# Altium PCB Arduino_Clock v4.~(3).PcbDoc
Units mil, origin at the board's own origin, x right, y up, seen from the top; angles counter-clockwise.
Board outline 6000 x 4000 mil, 2 copper layers (Top Layer, Bottom Layer); 29 components, 36 nets, 120 pads, 14 vias.
Unrouted connection lines stored in the file: 76.

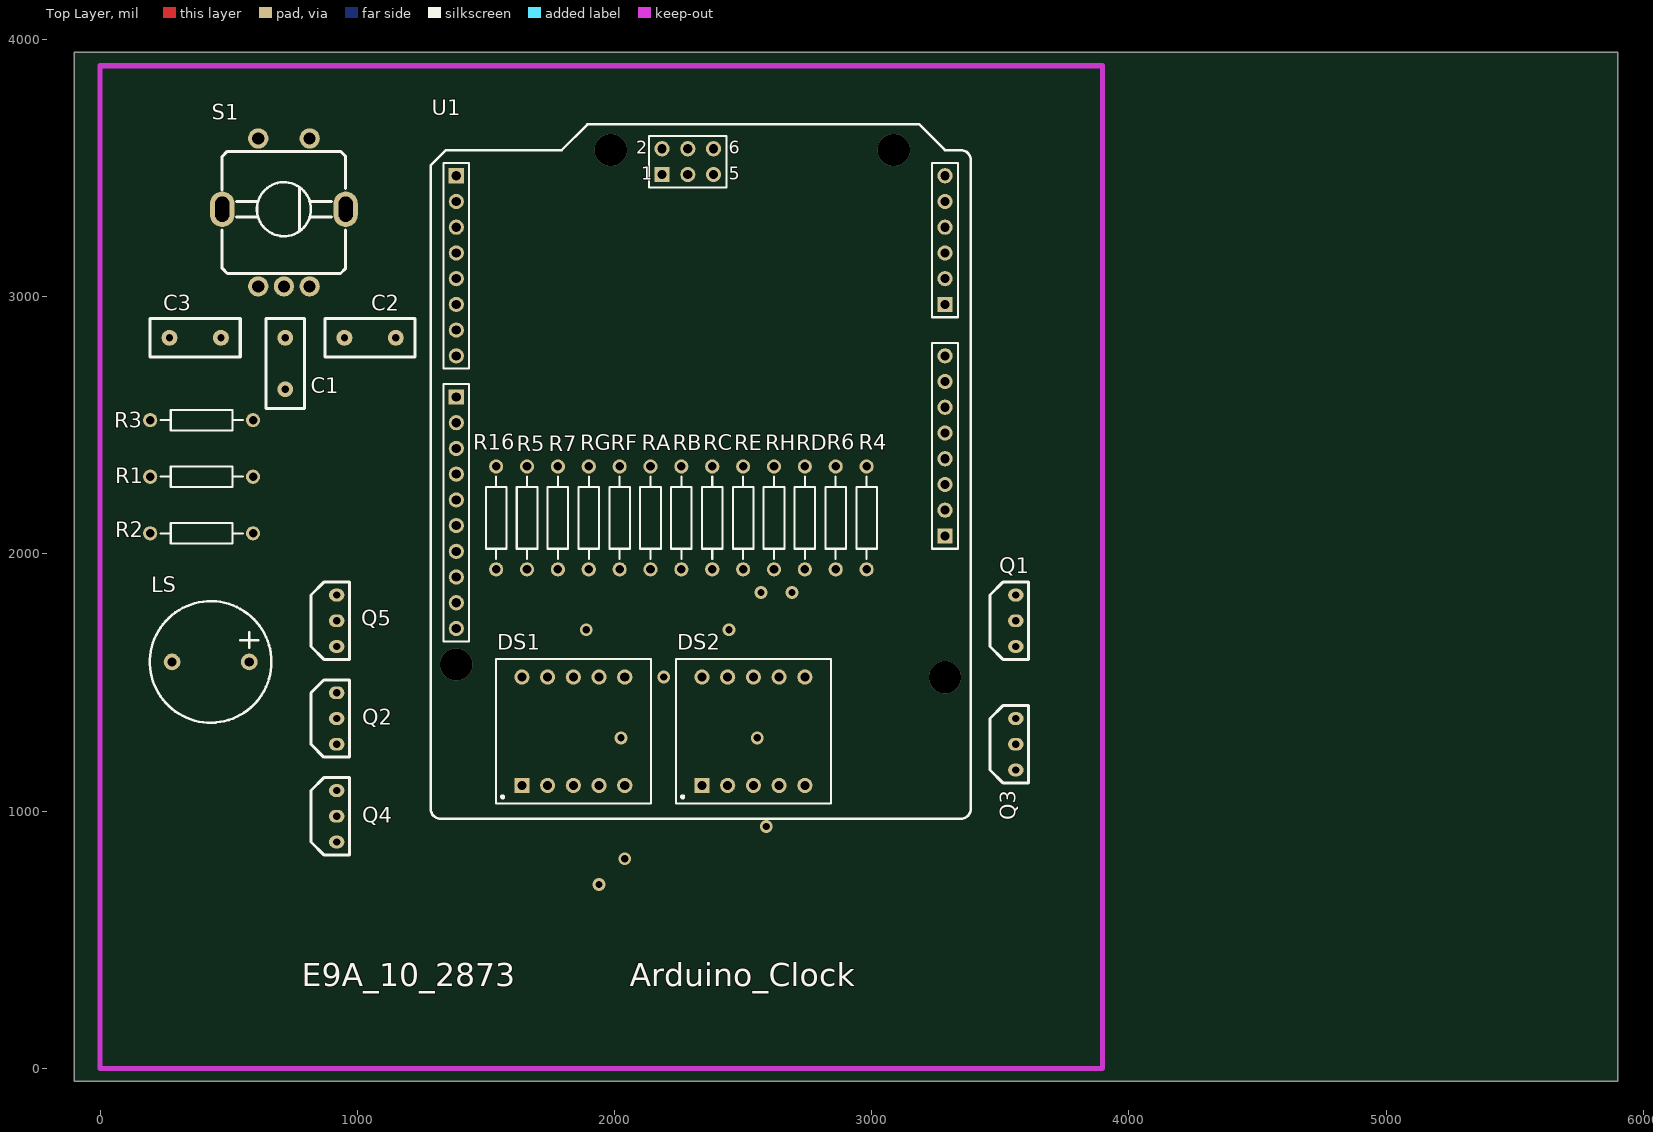
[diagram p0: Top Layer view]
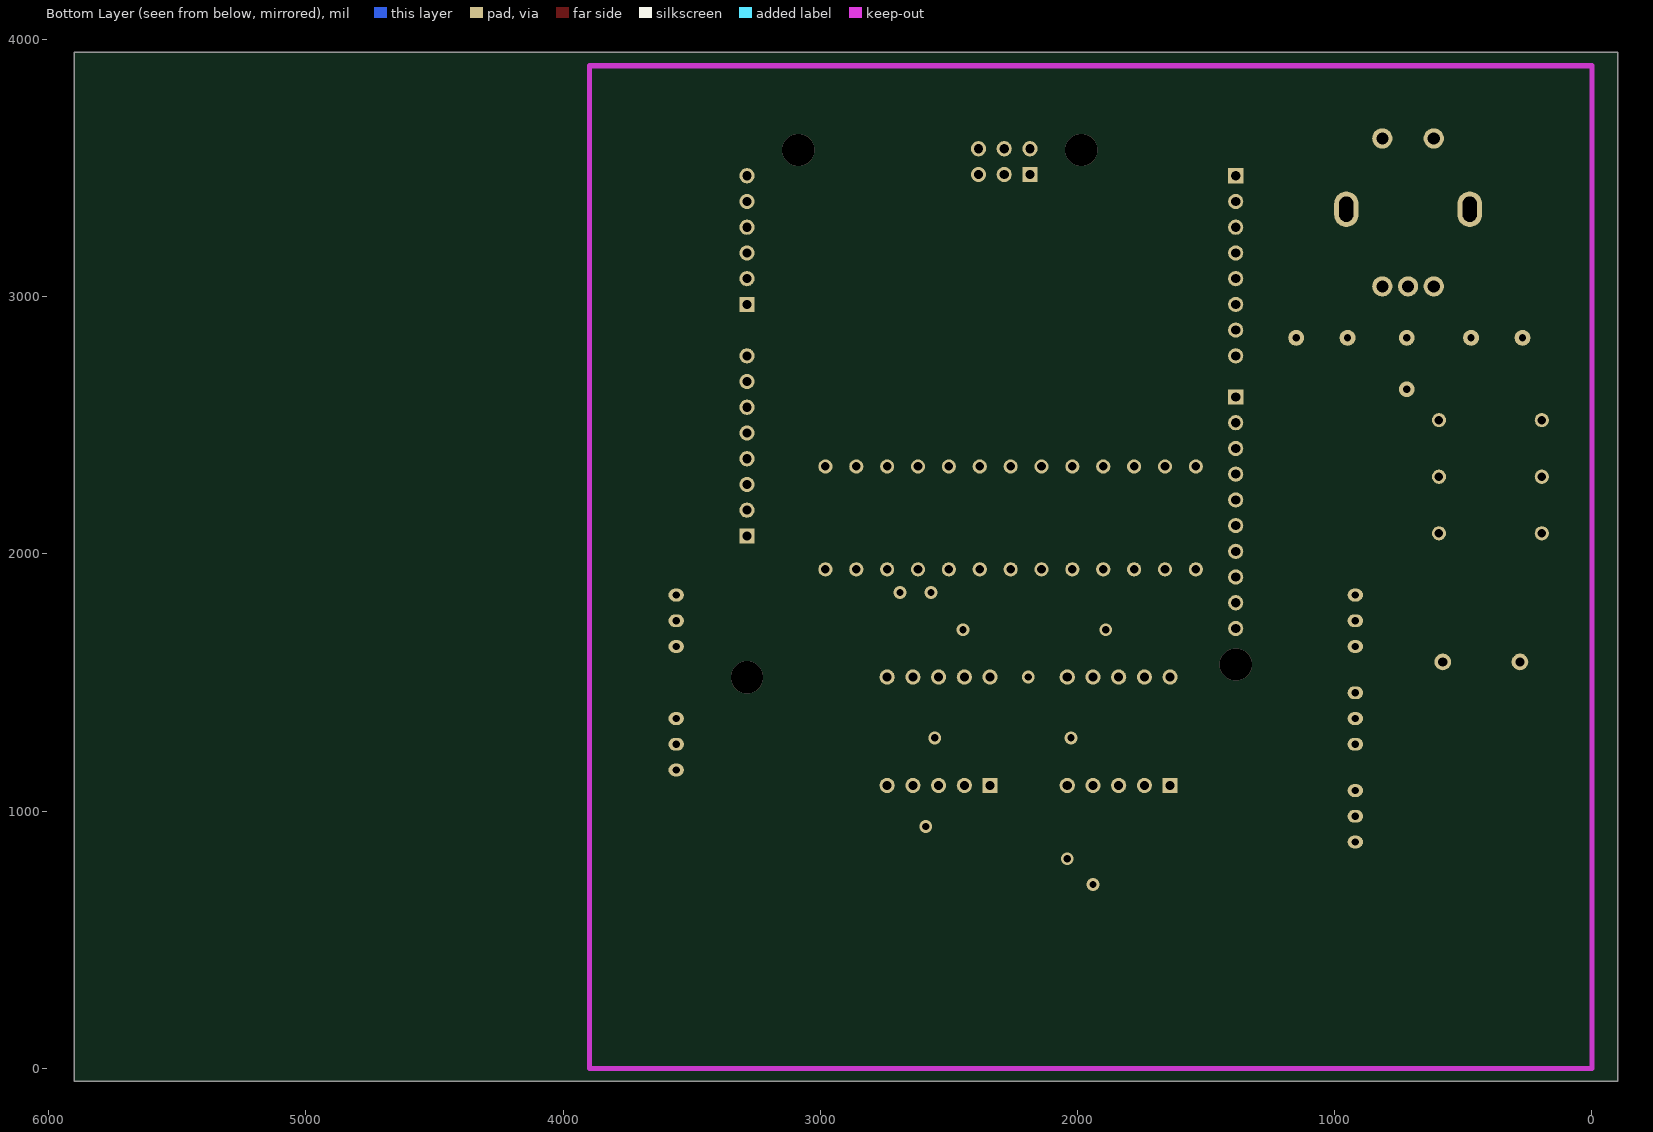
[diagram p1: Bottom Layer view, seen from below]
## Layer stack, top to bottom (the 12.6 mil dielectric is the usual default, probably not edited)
Top Layer: signal copper 1.4
Dielectric: dielectric 12.6, FR-4, Dk 4.8
Bottom Layer: signal copper 1.4

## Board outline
-100,-50 5900,-50 5900,3950 -100,3950

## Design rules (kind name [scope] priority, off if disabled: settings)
Clearance [All] p1 off: gap=10
DiffPairsRouting [All] p1 off: maxlimit=10 minlimit=10 mostfreqgap=10 maxuncoupledlength=500
FanoutControl Fanout_BGA [IsBGA] p1 off: bgadir=Out bgaviamode=Centered fanoutstyle=Auto fanoutdirection=Alternating viagrid=1 // Fanout_BGA (Default Rule)
FanoutControl Fanout_LCC [IsLCC] p2 off: bgadir=Out bgaviamode=Centered fanoutstyle=Auto fanoutdirection=Alternating viagrid=1 // Fanout_LCC (Default Rule)
FanoutControl Fanout_SOIC [IsSOIC] p3 off: bgadir=Out bgaviamode=Centered fanoutstyle=Auto fanoutdirection=Alternating viagrid=1 // Fanout_SOIC (Default Rule)
FanoutControl Fanout_Small [(CompPinCount < 5)] p4 off: bgadir=Out bgaviamode=Centered fanoutstyle=Auto fanoutdirection=OutThenIn viagrid=1 // Fanout_Small (Default Rule)
FanoutControl Fanout_Default [All] p5 off: bgadir=Out bgaviamode=Centered fanoutstyle=Auto fanoutdirection=Alternating viagrid=1 // Fanout_Default (Default Rule)
HoleSize [All] p1 off: absolutevalues=TRUE maxlimit=100 minlimit=1 maxpercent=80.000 minpercent=20.000
HoleToHoleClearance [All] p1 off: gap=10 allowstackedmicrovias=TRUE
LayerPairs [All] p1 off: enforce=TRUE
MinimumSolderMaskSliver [All] p1 off: minsoldermaskwidth=10
NetAntennae [All] p1 off: netantennaetolerance=0
PolygonConnect [All] p1: connectstyle=Relief reliefconductorwidth=10 reliefentries=4 polygonreliefangle="90 Angle"
RoomDefinition "Arduino_Clock v2" [InComponentClass('Arduino_Clock v2')] p1: confinementstyle=ConfineIn formatcopy=TRUE lockcomponents=FALSE outline 5825,-125 14900,-125 14900,2725 5825,2725
RoutingCorners [All] p1 off: cornerstyle=45-Degree minsetback=100 maxsetback=100
RoutingLayers [All] p1 off: top layer_v5=TRUE bottom layer_v5=TRUE
RoutingPriority [All] p1 off: routingpriority=0
RoutingTopology [All] p1 off: topology=Shortest
RoutingVias [All] p1 off: holewidth=28 width=50 viastyle="Through Hole" minholewidth=28 minwidth=50 maxholewidth=28 maxwidth=50
ShortCircuit [All] p1 off: allowed=FALSE
SilkToSilkClearance [All] p1 off: silktosilkclearance=10
SilkscreenOverComponentPads [All] p1 off: minsilkscreentomaskgap=10
SolderMaskExpansion [All] p1: expansion=4
TestPointUsage [All] p1 off: valid=0 allowmultiple=FALSE
Testpoint [All] p1 off: side=15 testpointundercomponent=TRUE minsize=40 maxsize=100 preferedsize=60 minholesize=0 maxholesize=40 preferedholesize=32 testpointgrid=1 style=1023 order=0123456789
UnRoutedNet [All] p1 off:
Width [All] p1 off: maxlimit=50 minlimit=10 preferedwidth=10
5 further rules are at their usual default settings.

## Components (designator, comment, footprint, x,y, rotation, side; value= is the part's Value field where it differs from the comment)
C1 "Cap" RAD0.2 720,2840 r270 top
C2 "Cap" RAD0.2 950,2840 r0 top
C3 "Cap" RAD0.2 470,2840 r180 top
DS1 "2-DigitDPY" 2-DigitDPY 1640,1100 r0 top
DS2 "2-DigitDPY" 2-DigitDPY 2340,1100 r0 top
LS "Buzzer" Buzzer 580,1580 r180 top
Q1 "NPN" NPN 3560,1640 r90 top
Q2 "NPN" NPN 920,1260 r90 top
Q3 "NPN" NPN 3560,1160 r90 top
Q4 "NPN" NPN 920,880 r90 top
Q5 "NPN" NPN 920,1640 r90 top
R1 "Res2" AXIAL-0.4 395,2300 r0 top
R2 "Res2" AXIAL-0.4 395,2080 r0 top
R3 "Res2" AXIAL-0.4 395,2520 r180 top
R4 "Res2" AXIAL-0.4 2980,2140 r90 top
R5 "Res2" AXIAL-0.4 1660,2140 r270 top
R6 "Res2" AXIAL-0.4 2860,2140 r90 top
R7 "Res2" AXIAL-0.4 1780,2140 r90 top
R16 "Res2" AXIAL-0.4 1540,2140 r270 top
RA "Res2" AXIAL-0.4 2140,2140 r270 top
RB "Res2" AXIAL-0.4 2260,2140 r270 top
RC "Res2" AXIAL-0.4 2380,2140 r270 top
RD "Res2" AXIAL-0.4 2740,2140 r270 top
RE "Res2" AXIAL-0.4 2500,2140 r270 top
RF "Res2" AXIAL-0.4 2020,2140 r270 top
RG "Res2" AXIAL-0.4 1900,2140 r270 top
RH "Res2" AXIAL-0.4 2620,2140 r270 top
S1 "SW-EC11" EC11 715,3340 r0 top
U1 "Arduino" Arduino-UNO 2335,2610 r90 top

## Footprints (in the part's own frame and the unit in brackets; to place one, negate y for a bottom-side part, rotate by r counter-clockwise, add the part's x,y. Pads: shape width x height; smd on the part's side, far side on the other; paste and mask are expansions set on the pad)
2-DigitDPY [mm] "LED, 7-Segment Display, 9.2 mm, Dual Digit; 10 Leads; Row Space 10.7 mm; Pitch 2.54 mm"
  rect 1.5x1.5 hole 0.9: 1(0,0)
  round 1.5 hole 0.9: 2(2.54,0) 3(5.08,0) 4(7.62,0) 5(10.16,0) 6(10.16,10.7) 7(7.62,10.7) 8(5.08,10.7) 9(2.54,10.7) 10(0,10.7)
  silkscreen extent -2.57,-1.8 12.73,12.5
Arduino-UNO [mm] "Arduino板"
  rect 1.5x1.5 hole 0.9: 1(21.844,24.13) 1(21.971,3.81) 9(0,24.13) 19(-13.716,-24.13) 27(9.144,-24.13)
  round 1.5 hole 0.9: 2(19.304,24.13) 2(24.511,3.81) 3(16.764,24.13) 3(21.971,1.27) 4(14.224,24.13) 4(24.511,1.27) 5(11.684,24.13) 5(21.971,-1.27) 6(9.144,24.13) 6(24.511,-1.27) 7(6.604,24.13) 8(4.064,24.13) 10(-2.54,24.13) 11(-5.08,24.13) 12(-7.62,24.13) 13(-10.16,24.13) 14(-12.7,24.13) 15(-15.24,24.13) 16(-17.78,24.13) 17(-20.32,24.13) 18(-22.86,24.13) 20(-11.176,-24.13) 21(-8.636,-24.13) 22(-6.096,-24.13) 23(-3.556,-24.13) 24(-1.016,-24.13) 25(1.524,-24.13) 26(4.064,-24.13) 28(11.684,-24.13) 29(14.224,-24.13) 30(16.764,-24.13) 31(19.304,-24.13) 32(21.844,-24.13)
  silkscreen extent -41.66,-26.67 26.92,26.67
AXIAL-0.4 [mm] "Resistor; 2 Leads"
  round 1.4 hole 0.85: 1(-5.08,0) 2(5.08,0)
  silkscreen extent -4.06,-1.02 4.06,1.02
Buzzer [mil] "蜂鸣器"
  round 65 hole 36: 1(0,0) 2(300,0)
  silkscreen extent -86,-236 386,236
EC11 [mm] "旋转编码器"
  round 2 hole 1.2: 1(-2.54,-7.62) 2(0,-7.62) 3(2.54,-7.62) 4(2.54,6.985) 5(-2.54,6.985)
  oval 2.4x3.5 hole 1.4 slot 2.5 at 90 deg: 6(-6.096,0) 7(6.096,0)
  silkscreen extent -6.1,-6.35 6.1,5.71
NPN [mil]
  oval 50x60 hole 28: 1(0,0) 2(100,0) 3(200,0)
  silkscreen extent -50,-50 250,100
RAD0.2 [mil]
  round 62 hole 28: 1(0,0) 2(200,0)
  silkscreen extent -75,-75 275,75

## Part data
C1 C2 C3: "Capacitor"
DS1 DS2: "9.2 mm Green 7-Segment Display: 2-Digit, RH DP"
LS: "Magnetic Transducer Buzzer"
Q1 Q2 Q3 Q4 Q5: "NPN Bipolar Transistor"
R1 R2 R3 R4 R5 R6 R7 R16 RA RB RC RD RE RF RG RH: "Resistor"
S1: "旋转编码开关"
U1: library part Arduino-UNO

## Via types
v1: diameter 50, hole 28, Top Layer to Bottom Layer, 10 vias
v2: diameter 125.98, hole 125.98, Top Layer to Bottom Layer, 4 vias

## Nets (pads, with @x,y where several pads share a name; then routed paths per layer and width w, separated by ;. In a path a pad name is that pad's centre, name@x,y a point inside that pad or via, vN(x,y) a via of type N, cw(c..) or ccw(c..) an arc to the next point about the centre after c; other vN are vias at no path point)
5V: LS.2 R1.1 R2.1 R3.2 U1.23
A: DS1.3 DS2.3 RA.2
  other v1: 1940,715
B: DS1.9 DS2.9 RB.2
C: DS1.8 DS2.8 RC.2
  other v1: 1890,1705 2445,1705
D: DS1.6 DS2.6 RD.2
D2: RB.1 U1.3
D3: RA.1 U1.4
D4: RF.1 U1.5
D5: RG.1 U1.6
D6: R7.2 U1.7
D7: R5.1 U1.8
D8: C1.2 R1.2 S1.1 U1.9
D9: C3.2 R3.1 S1.5 U1.10
D10: C2.2 R2.2 S1.3 U1.11
D11: R16.1 U1.12
D14: R4.2 U1.27
D15: R6.2 U1.28
D16: RD.1 U1.29
D17: RH.1 U1.30
D18: RE.1 U1.31
D19: RC.1 U1.32
E: DS1.7 DS2.7 RE.2
  other v1: 2025,1285 2555,1285
F: DS1.4 DS2.4 RF.2
G: DS1.1 DS2.1 RG.2
GND: C1.1 C2.1 C3.1 Q1.3 Q2.3 Q3.3 Q4.3 Q5.3 S1.2 S1.4 U1.15
NetDS1_2: DS1.2 DS2.2 RH.2
NetDS1_5: DS1.5 Q2.1
  other v1: 2040,815
NetDS1_10: DS1.10 Q1.1
  other v1: 2570,1850 2690,1850
NetDS2_5: DS2.5 Q4.1
NetDS2_10: DS2.10 Q3.1
  other v1: 2590,940 2191.26,1521.26
NetLS_1: LS.1 Q5.1
NetQ1_2: Q1.2 R4.1
NetQ2_2: Q2.2 R5.2
NetQ3_2: Q3.2 R6.1
NetQ4_2: Q4.2 R7.1
NetQ5_2: Q5.2 R16.2
pads on no net: S1.6 S1.7 U1.1 U1.2 U1.13 U1.14 U1.16 U1.17 U1.18 U1.19 U1.20 U1.21 U1.22 U1.24 U1.25 U1.26
copper on no net:
  other v2: 3285,1520 1385,1570 1985,3570 3085,3570

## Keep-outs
Keep-Out Layer:
  lines w20: 0,0 3897.64,0 3897.64,3897.64 0,3897.64 0,0

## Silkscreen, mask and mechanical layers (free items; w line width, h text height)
Top Overlay:
  text "E9A_10_2873" at 785,320 h90
  text "Arduino_Clock" at 2060,320 h90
